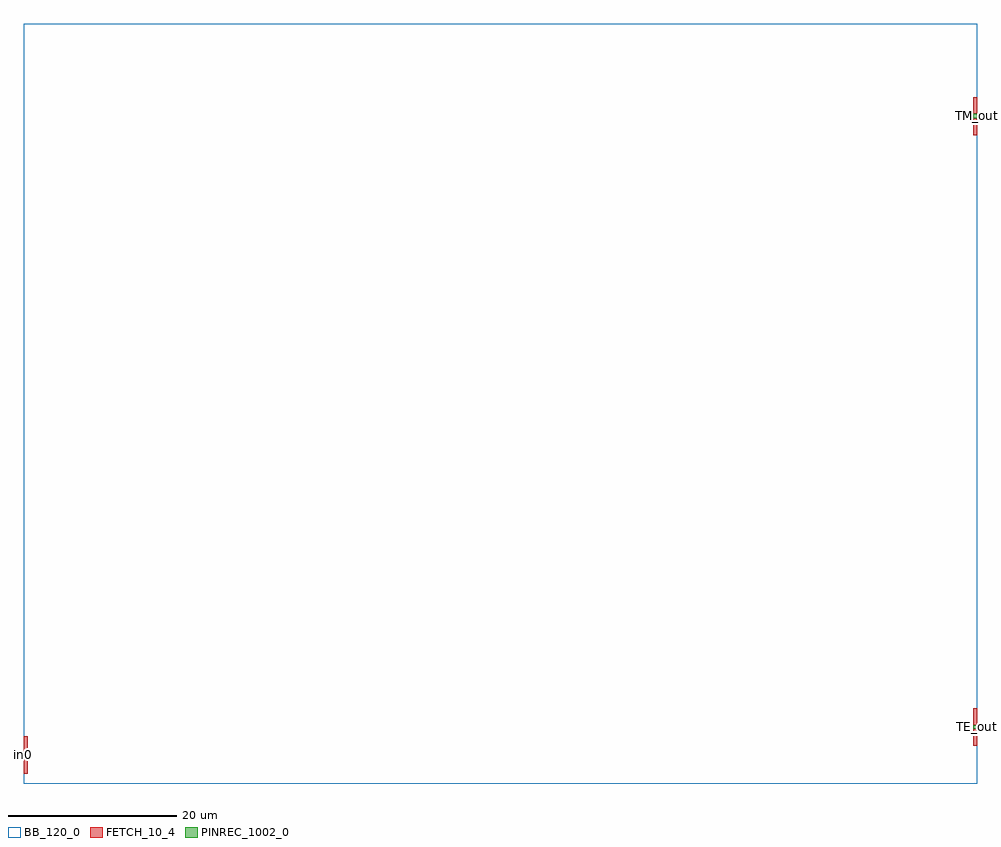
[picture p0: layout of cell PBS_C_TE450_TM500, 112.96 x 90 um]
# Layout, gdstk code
import gdstk
lib = gdstk.Library(unit=1e-6, precision=1e-09)
def R(c, l, rs):  # rectangles x0, y0, x1, y1
    for r in rs: c.add(gdstk.rectangle(r[:2], r[2:], *l))
FETCH_10_4 = (10, 4)
BB_120_0 = (120, 0)
PINREC_1002_0 = (1002, 0)

pbs_c_te450_tm500 = lib.new_cell('PBS_C_TE450_TM500')
R(pbs_c_te450_tm500, FETCH_10_4, [(0,1.161,0.5,3.161), (0,3.611,0.5,5.611), (112.46,4.454,112.96,6.454), (112.46,6.904,112.96,8.904), (112.46,76.791,112.96,78.791), (112.46,79.291,112.96,81.291)])
R(pbs_c_te450_tm500, BB_120_0, [(0,0,112.96,90)])
R(pbs_c_te450_tm500, PINREC_1002_0, [(0,3.161,0.5,3.611), (112.46,6.454,112.96,6.904), (112.46,78.791,112.96,79.291)])
pbs_c_te450_tm500.add(gdstk.Label('TM_out', (112.96,79.054), layer=1000, texttype=0))
pbs_c_te450_tm500.add(gdstk.Label('TE_out', (112.96,6.701), layer=1000, texttype=0))
pbs_c_te450_tm500.add(gdstk.Label('in0', (0,3.401), layer=1000, texttype=0))

lib.write_gds('PBS_C_TE450_TM500.gds')
